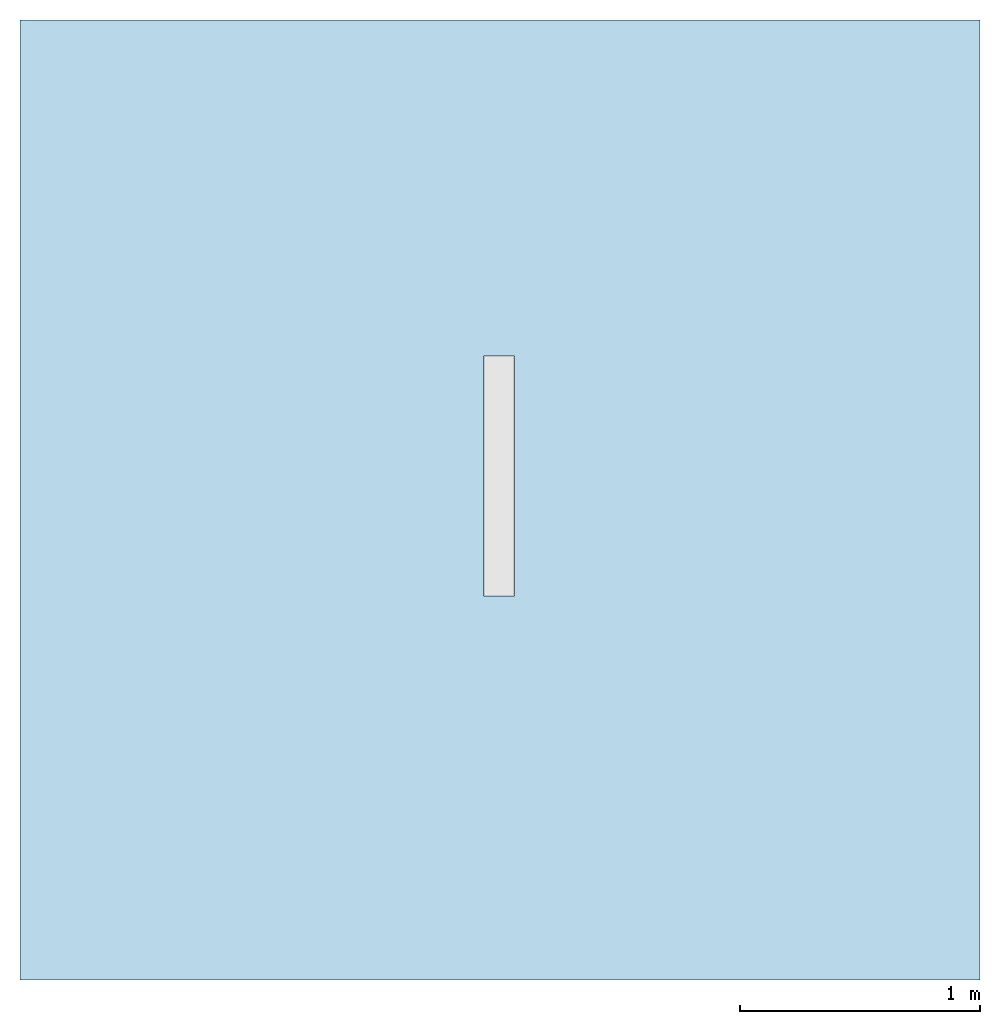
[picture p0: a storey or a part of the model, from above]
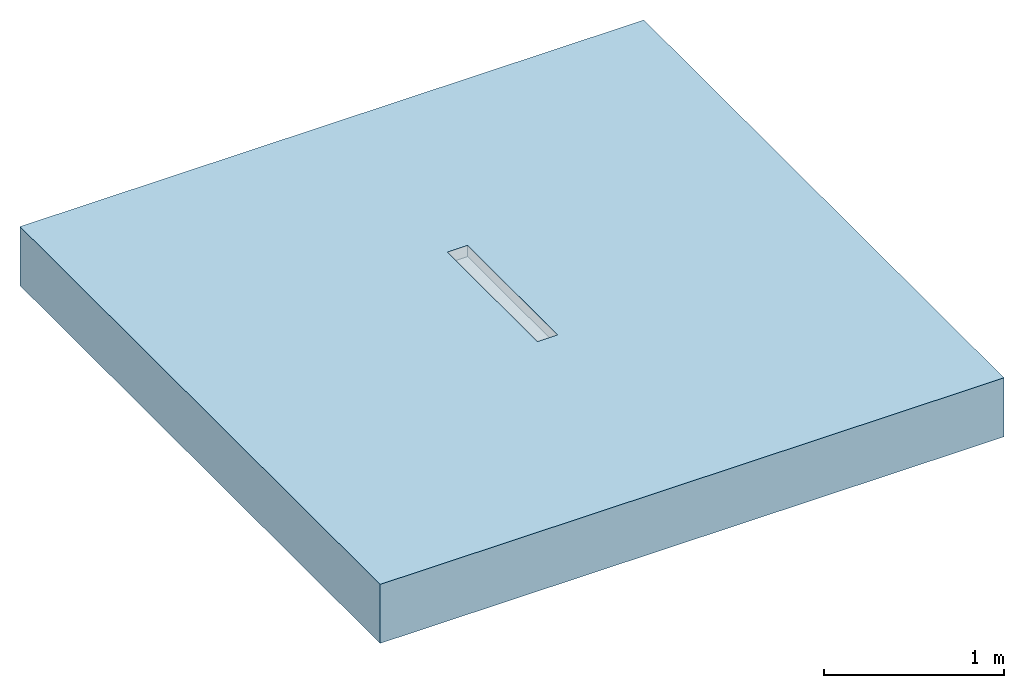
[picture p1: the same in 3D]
Properties of the parts of a building model (IFC2X3)

# File
Description: ViewDefinition [CoordinationView]
File name: Project Number
Time: 2014-06-06T14:57:18
Written by: The EXPRESS Data Manager Version 5.01.0100.02.64mod : 6 Jun 2012
Made in: 20130308_1515(x64) - Exporter 2014.0.2013.0308 - Default UI
Comment: STEP Physical File produced by: The EXPRESS Data Manager Version 5.01.0100.02.64mod : 6 Jun 2012 * Module: EDMstepFileFactory/EDMstandAlone * Creation date: Fri Jun 06 14:57:18 2014 * Host: IN-BLR-PC-0010 * Database: C:\Users\palleri\AppData\Local\Temp\{1DC927C9-84A0-4835-8F46-B06217D95CDF}\ifc * Database version: 5507 * Database creation date: Fri Jun 06 14:57:17 2014 * Schema: IFC2X3 * Model: DataRepository.ifc * Model creation date: Fri Jun 06 14:57:17 2014 * Header model: DataRepository.ifc_HeaderModel * Header model creation date: Fri Jun 06 14:57:17 2014 * EDMuser: sdai-user * EDMgroup: sdai-group * License ID and type: 5605 : Permanent license. Expiry date: * EDMstepFileFactory options: 020000

# IfcProject, Project Number
LongName: Project Name; Phase: Project Status

# IfcSite, Default
RefLatitude: 42, 21, 30, 344238; RefLongitude: -71, -3, -35, -194702; RefElevation: 0 mm

# IfcBuilding
Pset_BuildingCommon - NumberOfStoreys: 1
Other - Project Name: Project Name; Project Number: Project Number; Project Address: ## Street City, State Zip; Project Status: Project Status; Client Name: Owner; Project Issue Date: Issue Date

# IfcBuildingStorey, Level 1
LongName: Level 1; Elevation: 0 mm
Constraints - Elevation Base: Project Base Point; Elevation: 0 mm
Graphics - Color: 0; Symbol at End 2 Default: yes; Line Weight: 1; Line Pattern: Center; Symbol at End 1 Default: no; Symbol: M_Level Head - Circle: M_Level Head - Circle
Dimensions - Computation Height: 0 mm
Identity Data - Building Story: yes; Structural: no; Name: Level 1

# IfcFlowTerminal: 36981 - Fixed Height Channel - Shallow Section - 1000mm LG - Invert Depth 75mm, ACO Freedeck Fixed Height Channel Intermediate Section Galvanized Steel:36981 - Fixed Height Channel - Shallow Section - 1000mm LG - Invert Depth 75mm:310971
In: Level 1
Material: Galvanized Steel
Phasing - Phase Created: New Construction
Constraints - Moves With Nearby Elements: no; Level: Level: Level 1
Construction - 36953 - Grating - Plain Mesh - Galvanised Steel - 1000mm long: yes; 00277 - Grating - Slotted Grating - Galvanised Steel - 500mm long: no; End Plate Invert 2: no; 00276 - Grating - Slotted Grating - Galvanised Steel - 1000mm long: no; End Plate Invert 1: no; 36952 - Grating - Plain Mesh - Galvanised Steel - 500mm long: no
Identity Data - Mark: 28; Manufacturer: ACO Building Drainage; Website: www.acobd.com; Fax: +44 (0)1462 851490; Address: ACO Business Centre, Caxton Road, Bedford, MK41 0LF; Watermark1: This file is the property of ACO Technologies PLC; Watermarked With: BIM Manager Premium Suite; Watermark2: This file is water marked and users are prohibited to reproduce, adapt, distribute this information; Telephone: +44 (0)1462 816666; E-mail Sales: abdcommercial@aco.co.uk; E-mail Technical: abdtechnical@aco.co.uk; Watermarked By: www.acobd.com
Pset_ManufacturerTypeInformation - Manufacturer: ACO Building Drainage
Model Properties - Grating Product Code 00276: Load Class A15 - Slotted Grating - 10 x 80mm Slot - Galvanized Steel - 1000mm long - 2.2kg; Grating Product Code 00277: Load Class A15 - Slotted Grating - 10 x 80mm Slot - Galvanized Steel - 500mm long - 1.0kg; Grating Product Code 36952: Load Class A15 - Mesh Grating - 14mm x 30mm Mesh - Galvanized Steel - 500mm long - 1.6kg; Grating Product Code 36953: Load Class A15 - Mesh Grating - 14mm x 30mm Mesh - Galvanized Steel - 1000mm long - 3.0kg; End Plate Product Code 36983: End Plate - Galvanized Steel for Invert Depth - 75mm - 0.07Kg
Other - Side Void: 4; Nos: 32
General - Product Code: 36981; Maintenance Guidelines: X:\Electronic Literature\ABD Electronic Literature\Roof and Balcony Drainage\ACO Freedeck Brochure.pdf; Product Standard: BS EN 1433:2002, CE marked; Load Class: A15; NBS Specification: NBS Section R10 Gravity Rainwater Drainage Systems, Subsection 365; Product Range: ACO Freedeck; Dimensions (LxWxH): 1000 x 130 x 75; Weight (Kg): 2.65kg; Channel Recyclable: Fully recyclable; Product Type: Linear Deck Drainage System; Price: POA - contact ACO; Channel Material: Hot Dipped Galvanised Steel; Installation Guidelines: X:\Electronic Literature\ABD Electronic Literature\Roof and Balcony Drainage\ACO Freedeck Brochure.pdf; Channel Colour: Galvanised; Product Description: ACO FreeDeck Fixed Height Channel - Intermediate Section; Channel Recycled Material Content: 25 - 30 %
Materials and Finishes - Material: Galvanized Steel
Dimensions - Grating End Length: 1000 mm; Height: 75 mm; Channel End Length: -1000 mm

# IfcSlab: Floor:Generic Floor - 400mm, Floor:Generic Floor - 400mm:193825
In: Level 1
PredefinedType: FLOOR; Material: Concrete, Broom Finish 400 mm
Constraints - Level: Level: Level 1; Height Offset From Level: 0 mm; Related to Mass: no; Room Bounding: yes
Dimensions - Volume: 6.39025 m3; Perimeter: 16000 mm; Thickness: 400 mm; Area: 16 m2
Structural - Structural: no; Enable Analytical Model: no
Phasing - Phase Created: New Construction
Pset_SlabCommon - Reference: Generic Floor - 400mm; IsExternal: no; LoadBearing: yes; ThermalTransmittance: 2.615 kg/K/s3; PitchAngle: 0 deg
Graphics - Coarse Scale Fill Color: 0
Analytical Properties - Thermal mass: 604440; Roughness: 1; Thermal Resistance (R): 0.382409; Heat Transfer Coefficient (U): 2.615; Absorptance: 0.1
Materials and Finishes - Structural Material: Concrete, Broom Finish
Construction - Function: Interior; Default Thickness: 400 mm
